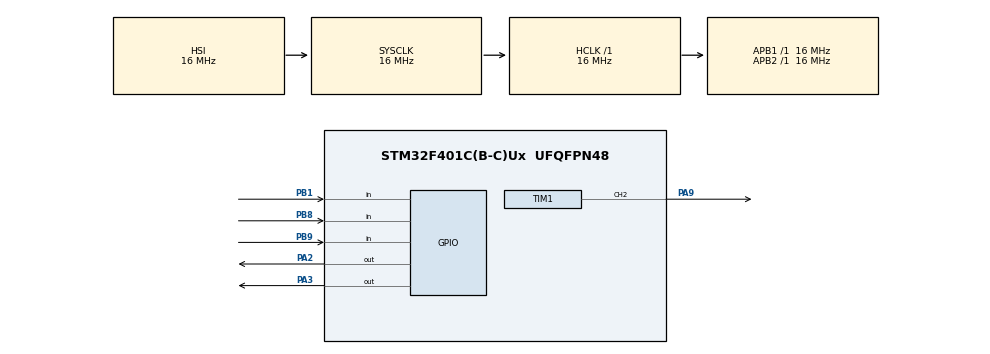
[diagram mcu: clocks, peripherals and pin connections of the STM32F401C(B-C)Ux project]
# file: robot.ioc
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Mcu.Family=STM32F4
Mcu.Name=STM32F401C(B-C)Ux
Mcu.Package=UFQFPN48
NVIC.PriorityGroup=NVIC_PRIORITYGROUP_4
PA2.Signal=GPIO_Output
PA3.Signal=GPIO_Output
PA9.Signal=S_TIM1_CH2
PB1.Signal=GPIO_Input
PB8.Signal=GPIO_Input
PB9.Signal=GPIO_Input
ProjectManager.HeapSize=0x200
ProjectManager.StackSize=0x400
ProjectManager.TargetToolchain=STM32CubeIDE
RCC.AHBFreq_Value=16000000
RCC.APB1Freq_Value=16000000
RCC.APB2Freq_Value=16000000
RCC.CortexFreq_Value=16000000
RCC.HSE_VALUE=25000000
RCC.HSI_VALUE=16000000
RCC.LSE_VALUE=32768
RCC.SYSCLKFreq_VALUE=16000000
RCC.VCOOutputFreq_Value=192000000
SH.S_TIM1_CH2.0=TIM1_CH2,PWM Generation2 CH2
TIM1.Channel-PWM\ Generation2\ CH2=TIM_CHANNEL_2
board=custom

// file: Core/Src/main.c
/* USER CODE BEGIN Header */
/**
  ******************************************************************************
  * @file           : main.c
  * @brief          : Main program body
  ******************************************************************************
  * @attention
  *
  * Copyright (c) 2026 STMicroelectronics.
  * All rights reserved.
  *
  * This software is licensed under terms that can be found in the LICENSE file
  * in the root directory of this software component.
  * If no LICENSE file comes with this software, it is provided AS-IS.
  *
  ******************************************************************************
  */
/* USER CODE END Header */
#include "main.h"

TIM_HandleTypeDef htim1;

void SystemClock_Config(void);
static void MX_GPIO_Init(void);
static void MX_TIM1_Init(void);
/* USER CODE BEGIN PFP */
void motor_forward()
{
    HAL_GPIO_WritePin(GPIOA, GPIO_PIN_1, GPIO_PIN_SET);    // AIN1
    HAL_GPIO_WritePin(GPIOA, GPIO_PIN_0, GPIO_PIN_RESET);  // AIN2
    HAL_GPIO_WritePin(GPIOA, GPIO_PIN_2, GPIO_PIN_SET);    // BIN1
    HAL_GPIO_WritePin(GPIOA, GPIO_PIN_3, GPIO_PIN_RESET);  // BIN2
}

void motor_backward()
{
    HAL_GPIO_WritePin(GPIOA, GPIO_PIN_1, GPIO_PIN_RESET);  // AIN1
    HAL_GPIO_WritePin(GPIOA, GPIO_PIN_0, GPIO_PIN_SET);    // AIN2
    HAL_GPIO_WritePin(GPIOA, GPIO_PIN_2, GPIO_PIN_RESET);  // BIN1
    HAL_GPIO_WritePin(GPIOA, GPIO_PIN_3, GPIO_PIN_SET);    // BIN2
}

void motor_stop()
{
    HAL_GPIO_WritePin(GPIOA, GPIO_PIN_1, GPIO_PIN_RESET);  // AIN1
    HAL_GPIO_WritePin(GPIOA, GPIO_PIN_0, GPIO_PIN_RESET);  // AIN2
    HAL_GPIO_WritePin(GPIOA, GPIO_PIN_2, GPIO_PIN_RESET);  // BIN1
    HAL_GPIO_WritePin(GPIOA, GPIO_PIN_3, GPIO_PIN_RESET);  // BIN2
}
/* USER CODE END PFP */

int main(void)
{
  HAL_Init();

  /* USER CODE BEGIN Init */
  // ✅ HAL_TIM_PWM_Start убран отсюда
  /* USER CODE END Init */

  SystemClock_Config();

  MX_GPIO_Init();
  MX_TIM1_Init();

  /* USER CODE BEGIN 2 */
  HAL_TIM_PWM_Start(&htim1, TIM_CHANNEL_2);
  __HAL_TIM_SET_COMPARE(&htim1, TIM_CHANNEL_2, 65530);
  /* USER CODE END 2 */

  while (1)
  {
      if (HAL_GPIO_ReadPin(GPIOB, GPIO_PIN_1) == GPIO_PIN_RESET ||
          HAL_GPIO_ReadPin(GPIOB, GPIO_PIN_0) == GPIO_PIN_RESET ||
		  HAL_GPIO_ReadPin(GPIOA, GPIO_PIN_4) == GPIO_PIN_RESET )
      {
          // препятствие — стоп
          motor_stop();
      }
      else
      {
          // путь свободен — вперёд
          motor_forward();
      }
      HAL_Delay(50);
  }
}

void SystemClock_Config(void)
{
  RCC_OscInitTypeDef RCC_OscInitStruct = {0};
  RCC_ClkInitTypeDef RCC_ClkInitStruct = {0};

  __HAL_RCC_PWR_CLK_ENABLE();
  __HAL_PWR_VOLTAGESCALING_CONFIG(PWR_REGULATOR_VOLTAGE_SCALE2);

  RCC_OscInitStruct.OscillatorType = RCC_OSCILLATORTYPE_HSI;
  RCC_OscInitStruct.HSIState = RCC_HSI_ON;
  RCC_OscInitStruct.HSICalibrationValue = RCC_HSICALIBRATION_DEFAULT;
  RCC_OscInitStruct.PLL.PLLState = RCC_PLL_NONE;
  if (HAL_RCC_OscConfig(&RCC_OscInitStruct) != HAL_OK)
    Error_Handler();

  RCC_ClkInitStruct.ClockType = RCC_CLOCKTYPE_HCLK|RCC_CLOCKTYPE_SYSCLK
                              |RCC_CLOCKTYPE_PCLK1|RCC_CLOCKTYPE_PCLK2;
  RCC_ClkInitStruct.SYSCLKSource = RCC_SYSCLKSOURCE_HSI;
  RCC_ClkInitStruct.AHBCLKDivider = RCC_SYSCLK_DIV1;
  RCC_ClkInitStruct.APB1CLKDivider = RCC_HCLK_DIV1;
  RCC_ClkInitStruct.APB2CLKDivider = RCC_HCLK_DIV1;

  if (HAL_RCC_ClockConfig(&RCC_ClkInitStruct, FLASH_LATENCY_0) != HAL_OK)
    Error_Handler();
}

static void MX_TIM1_Init(void)
{
  TIM_MasterConfigTypeDef sMasterConfig = {0};
  TIM_OC_InitTypeDef sConfigOC = {0};
  TIM_BreakDeadTimeConfigTypeDef sBreakDeadTimeConfig = {0};

  htim1.Instance = TIM1;
  htim1.Init.Prescaler = 0;
  htim1.Init.CounterMode = TIM_COUNTERMODE_UP;
  htim1.Init.Period = 65535;
  htim1.Init.ClockDivision = TIM_CLOCKDIVISION_DIV1;
  htim1.Init.RepetitionCounter = 0;
  htim1.Init.AutoReloadPreload = TIM_AUTORELOAD_PRELOAD_DISABLE;
  if (HAL_TIM_PWM_Init(&htim1) != HAL_OK)
    Error_Handler();

  sMasterConfig.MasterOutputTrigger = TIM_TRGO_RESET;
  sMasterConfig.MasterSlaveMode = TIM_MASTERSLAVEMODE_DISABLE;
  if (HAL_TIMEx_MasterConfigSynchronization(&htim1, &sMasterConfig) != HAL_OK)
    Error_Handler();
      sConfigOC.OCMode = TIM_OCMODE_PWM1;
  sConfigOC.Pulse = 0;
  sConfigOC.OCPolarity = TIM_OCPOLARITY_HIGH;
  sConfigOC.OCNPolarity = TIM_OCNPOLARITY_HIGH;
  sConfigOC.OCFastMode = TIM_OCFAST_DISABLE;
  sConfigOC.OCIdleState = TIM_OCIDLESTATE_RESET;
  sConfigOC.OCNIdleState = TIM_OCNIDLESTATE_RESET;
  if (HAL_TIM_PWM_ConfigChannel(&htim1, &sConfigOC, TIM_CHANNEL_2) != HAL_OK)
    Error_Handler();

  sBreakDeadTimeConfig.OffStateRunMode = TIM_OSSR_DISABLE;
  sBreakDeadTimeConfig.OffStateIDLEMode = TIM_OSSI_DISABLE;
  sBreakDeadTimeConfig.LockLevel = TIM_LOCKLEVEL_OFF;
  sBreakDeadTimeConfig.DeadTime = 0;
  sBreakDeadTimeConfig.BreakState = TIM_BREAK_DISABLE;
  sBreakDeadTimeConfig.BreakPolarity = TIM_BREAKPOLARITY_HIGH;
  sBreakDeadTimeConfig.AutomaticOutput = TIM_AUTOMATICOUTPUT_DISABLE;
  if (HAL_TIMEx_ConfigBreakDeadTime(&htim1, &sBreakDeadTimeConfig) != HAL_OK)
    Error_Handler();

  HAL_TIM_MspPostInit(&htim1);
}

static void MX_GPIO_Init(void)
{
  GPIO_InitTypeDef GPIO_InitStruct = {0};

  __HAL_RCC_GPIOA_CLK_ENABLE();
  __HAL_RCC_GPIOB_CLK_ENABLE();

  HAL_GPIO_WritePin(GPIOA, GPIO_PIN_0|GPIO_PIN_1|GPIO_PIN_2|GPIO_PIN_3, GPIO_PIN_RESET);
  HAL_GPIO_WritePin(GPIOA, GPIO_PIN_8, GPIO_PIN_SET);  // PWMA всегда HIGH

  GPIO_InitStruct.Pin = GPIO_PIN_0|GPIO_PIN_1|GPIO_PIN_2|GPIO_PIN_3|GPIO_PIN_8;
  GPIO_InitStruct.Mode = GPIO_MODE_OUTPUT_PP;
  GPIO_InitStruct.Pull = GPIO_NOPULL;
  GPIO_InitStruct.Speed = GPIO_SPEED_FREQ_LOW;
  HAL_GPIO_Init(GPIOA, &GPIO_InitStruct);

  GPIO_InitStruct.Pin = GPIO_PIN_4;
  GPIO_InitStruct.Mode = GPIO_MODE_INPUT;
  GPIO_InitStruct.Pull = GPIO_NOPULL;
  HAL_GPIO_Init(GPIOA, &GPIO_InitStruct);

  GPIO_InitStruct.Pin = GPIO_PIN_0|GPIO_PIN_1|GPIO_PIN_8|GPIO_PIN_9;
  GPIO_InitStruct.Mode = GPIO_MODE_INPUT;
  GPIO_InitStruct.Pull = GPIO_NOPULL;
  HAL_GPIO_Init(GPIOB, &GPIO_InitStruct);
}

void Error_Handler(void)
{
  __disable_irq();
  while (1) {}
}
